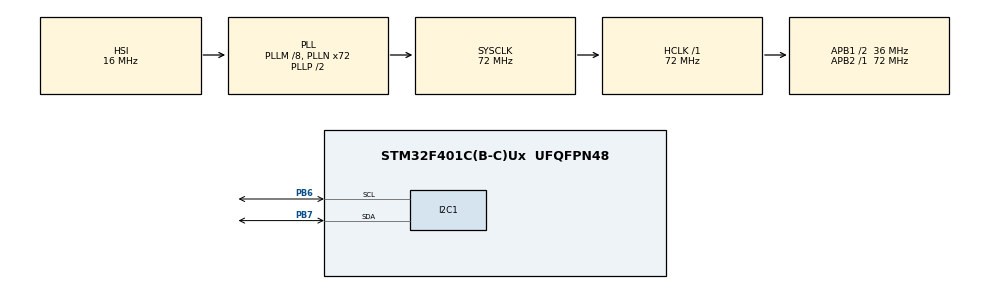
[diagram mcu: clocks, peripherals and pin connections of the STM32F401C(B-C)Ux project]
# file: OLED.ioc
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Mcu.Family=STM32F4
Mcu.Name=STM32F401C(B-C)Ux
Mcu.Package=UFQFPN48
NVIC.PriorityGroup=NVIC_PRIORITYGROUP_4
PA13.Mode=Serial_Wire
PA13.Signal=SYS_JTMS-SWDIO
PA14.Mode=Serial_Wire
PA14.Signal=SYS_JTCK-SWCLK
PB6.Mode=I2C
PB6.Signal=I2C1_SCL
PB7.Mode=I2C
PB7.Signal=I2C1_SDA
PH0\ -\ OSC_IN.Mode=HSE-External-Oscillator
PH0\ -\ OSC_IN.Signal=RCC_OSC_IN
PH1\ -\ OSC_OUT.Mode=HSE-External-Oscillator
PH1\ -\ OSC_OUT.Signal=RCC_OSC_OUT
ProjectManager.HeapSize=0x200
ProjectManager.StackSize=0x400
ProjectManager.TargetToolchain=STM32CubeIDE
RCC.48MHZClocksFreq_Value=36000000
RCC.AHBFreq_Value=72000000
RCC.APB1CLKDivider=RCC_HCLK_DIV2
RCC.APB1Freq_Value=36000000
RCC.APB1TimFreq_Value=72000000
RCC.APB2Freq_Value=72000000
RCC.APB2TimFreq_Value=72000000
RCC.CortexFreq_Value=72000000
RCC.HCLKFreq_Value=72000000
RCC.HSE_VALUE=25000000
RCC.HSI_VALUE=16000000
RCC.LSE_VALUE=32768
RCC.PLLM=8
RCC.PLLN=72
RCC.SYSCLKFreq_VALUE=72000000
RCC.SYSCLKSource=RCC_SYSCLKSOURCE_PLLCLK
RCC.VCOOutputFreq_Value=144000000
board=custom

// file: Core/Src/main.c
/* USER CODE BEGIN Header */
/**
  ******************************************************************************
  * @file           : main.c
  * @brief          : Main program body
  ******************************************************************************
  * @attention
  *
  * Copyright (c) 2024 STMicroelectronics.
  * All rights reserved.
  *
  * This software is licensed under terms that can be found in the LICENSE file
  * in the root directory of this software component.
  * If no LICENSE file comes with this software, it is provided AS-IS.
  *
  ******************************************************************************
  */
/* USER CODE END Header */
#include "main.h"

/* USER CODE BEGIN Includes */

#include "OLED.h"

/* USER CODE END Includes */

I2C_HandleTypeDef hi2c1;

void SystemClock_Config(void);
static void MX_GPIO_Init(void);
void ReadInputs();

int main(void)
{

  /* MCU Configuration--------------------------------------------------------*/

  /* Reset of all peripherals, Initializes the Flash interface and the Systick. */
  HAL_Init();

  /* Configure the system clock */
  SystemClock_Config();

  /* Initialize all configured peripherals */
  MX_GPIO_Init();
  MX_I2C1_Init();
  /* USER CODE BEGIN 2 */

  SSD1306_Init();  // initialise
  SSD1306_Fill(0);
  SSD1306_GotoXY(0,0); SSD1306_Puts ("FARESPCB Co", get_Font_11x18(), 1);
  SSD1306_GotoXY(0,19);SSD1306_Puts ("Panda+ Kit ", get_Font_11x18(), 1);
  SSD1306_GotoXY(0,38);SSD1306_Puts ("STM32F401  ", get_Font_11x18(), 1);
  /* USER CODE END 2 */

  /* Infinite loop */
  /* USER CODE BEGIN WHILE */
  while (1)
  {
	  ReadInputs();

	   SSD1306_UpdateScreen();

    /* USER CODE END WHILE */

  }
}

void SystemClock_Config(void)
{
  RCC_OscInitTypeDef RCC_OscInitStruct = {0};
  RCC_ClkInitTypeDef RCC_ClkInitStruct = {0};

  /** Configure the main internal regulator output voltage
  */
  __HAL_RCC_PWR_CLK_ENABLE();
  __HAL_PWR_VOLTAGESCALING_CONFIG(PWR_REGULATOR_VOLTAGE_SCALE2);
  /** Initializes the RCC Oscillators according to the specified parameters
  * in the RCC_OscInitTypeDef structure.
  */
  RCC_OscInitStruct.OscillatorType = RCC_OSCILLATORTYPE_HSI;
  RCC_OscInitStruct.HSIState = RCC_HSI_ON;
  RCC_OscInitStruct.HSICalibrationValue = RCC_HSICALIBRATION_DEFAULT;
  RCC_OscInitStruct.PLL.PLLState = RCC_PLL_ON;
  RCC_OscInitStruct.PLL.PLLSource = RCC_PLLSOURCE_HSI;
  RCC_OscInitStruct.PLL.PLLM = 8;
  RCC_OscInitStruct.PLL.PLLN = 72;
  RCC_OscInitStruct.PLL.PLLP = RCC_PLLP_DIV2;
  RCC_OscInitStruct.PLL.PLLQ = 4;
  if (HAL_RCC_OscConfig(&RCC_OscInitStruct) != HAL_OK)
  {
    Error_Handler();
  }
  /** Initializes the CPU, AHB and APB buses clocks
  */
  RCC_ClkInitStruct.ClockType = RCC_CLOCKTYPE_HCLK|RCC_CLOCKTYPE_SYSCLK
                              |RCC_CLOCKTYPE_PCLK1|RCC_CLOCKTYPE_PCLK2;
  RCC_ClkInitStruct.SYSCLKSource = RCC_SYSCLKSOURCE_PLLCLK;
  RCC_ClkInitStruct.AHBCLKDivider = RCC_SYSCLK_DIV1;
  RCC_ClkInitStruct.APB1CLKDivider = RCC_HCLK_DIV2;
  RCC_ClkInitStruct.APB2CLKDivider = RCC_HCLK_DIV1;

  if (HAL_RCC_ClockConfig(&RCC_ClkInitStruct, FLASH_LATENCY_2) != HAL_OK)
  {
    Error_Handler();
  }
}

static void MX_GPIO_Init(void)
{

  /* GPIO Ports Clock Enable */
  __HAL_RCC_GPIOH_CLK_ENABLE();
  __HAL_RCC_GPIOA_CLK_ENABLE();
  __HAL_RCC_GPIOB_CLK_ENABLE();

  /*Configure GPIO pin Output Level */
  HAL_GPIO_WritePin(GPIOA, DO_Row1_Pin|DO_Row2_Pin|DO_Row3_Pin|DO_Row4_Pin, GPIO_PIN_RESET);

  HAL_GPIO_WritePin(GPIOB, DO_Buzzer_Pin, GPIO_PIN_RESET);
  /*Configure GPIO pins : DO_Row1_Pin DO_Row2_Pin DO_Row3_Pin DO_Row4_Pin
                           DO_EN_Pin DO_RS_Pin */
  GPIO_InitTypeDef GPIO_InitStruct;

  GPIO_InitStruct.Pin = DO_Row1_Pin|DO_Row2_Pin|DO_Row3_Pin|DO_Row4_Pin;
  GPIO_InitStruct.Mode = GPIO_MODE_OUTPUT_PP;
  GPIO_InitStruct.Pull = GPIO_NOPULL;
  GPIO_InitStruct.Speed = GPIO_SPEED_FREQ_LOW;
  HAL_GPIO_Init(GPIOA, &GPIO_InitStruct);

  /*Configure GPIO pins : DI_Col4_Pin DI_Col3_Pin DI_Col1_Pin DI_Col2_Pin */
  GPIO_InitStruct.Pin = DI_Col4_Pin|DI_Col3_Pin|DI_Col1_Pin|DI_Col2_Pin;
  GPIO_InitStruct.Mode = GPIO_MODE_INPUT;
  GPIO_InitStruct.Pull = GPIO_PULLUP;
  HAL_GPIO_Init(GPIOB, &GPIO_InitStruct);

  /*Configure GPIO pins : DO_Buzzer_Pin */
   GPIO_InitStruct.Pin = DO_Buzzer_Pin;
   GPIO_InitStruct.Mode = GPIO_MODE_OUTPUT_PP;
   GPIO_InitStruct.Pull = GPIO_NOPULL;
   GPIO_InitStruct.Speed = GPIO_SPEED_FREQ_LOW;
   HAL_GPIO_Init(GPIOB, &GPIO_InitStruct);

}

void Error_Handler(void)
{
  __disable_irq();
  while (1)
  {
  }
}
